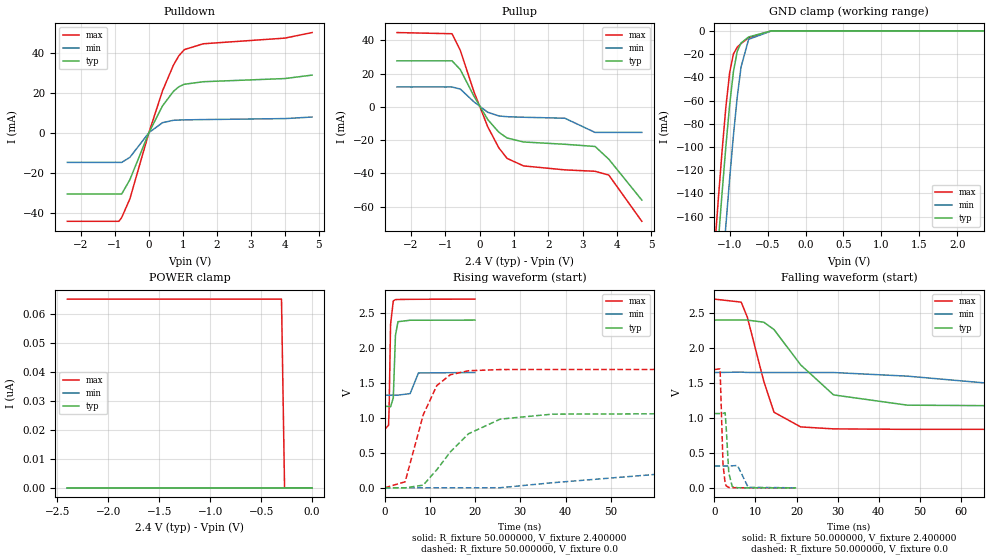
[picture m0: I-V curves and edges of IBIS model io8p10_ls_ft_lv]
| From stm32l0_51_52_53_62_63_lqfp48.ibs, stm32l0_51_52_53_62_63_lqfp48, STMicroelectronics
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|   Model io8p10_ls_ft_lv
[Model]  io8p10_ls_ft_lv
Model_type I/O
Polarity   Non-Inverting
Enable   Active-Low
Vinl =   0.720000V
Vinh =   1.680000V
Vmeas =  1.200000V
Cref =   50.000000pF
Rref =   100.000000M
Vref =   0.0V
C_comp   4.521100pF   4.438000pF   4.578000pF
[Temperature Range]   25.000000   0.105000k   -40.000000
[Pullup Reference]   2.400000V   1.650000V   2.700000V
[Pulldown Reference]   0.0V   0.0V   0.0V
[POWER Clamp Reference]   2.400000V   1.650000V   2.700000V
[GND Clamp Reference]   0.0V   0.0V   0.0V
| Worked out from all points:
|   slope of the pulldown table from 0 to 0.36 V, typ, clamps not added: 29.5 ohm
|   slope of the pullup table from 0 to 0.36 V, typ, clamps not added: 33.2 ohm
|   GND clamp passes 1 mA (typ) near -0.59 V on its own axis
|   rising waveform, R_fixture 50.000000, V_fixture 2.400000: 20-80 % time 360ps typ, 685ps min, 300ps max; typ from 1.17 V to 2.4 V
|   rising waveform, R_fixture 50.000000, V_fixture 0.0: 20-80 % time 9.31ns typ, 24.7ns min, 4.8ns max; typ from 0 V to 1.06 V
|   falling waveform, R_fixture 50.000000, V_fixture 2.400000: 20-80 % time 10.1ns typ, 27.3ns min, 5.05ns max; typ from 2.4 V to 1.17 V
|   falling waveform, R_fixture 50.000000, V_fixture 0.0: 20-80 % time 615ps typ, 996ps min, 511ps max; typ from 1.06 V to 0 V
[Pulldown]
|Voltage   I(typ)   I(min)   I(max)
-2.4V     -30.64mA   -14.84mA   -44.29mA
-880mV    -30.64mA   -14.84mA   -44.29mA
-800mV    -30.64mA   -14.84mA   -42.37mA
-560mV    -23.52mA   -12.34mA   -33.09mA
0V        -765.2nA   -61.1nA    -2.527uA
400mV     13.38mA    4.998mA    20.91mA
720mV     20.62mA    6.178mA    33.69mA
880mV     22.92mA    6.307mA    38.42mA
1.04V     24.19mA    6.385mA    41.49mA
1.6V      25.46mA    6.544mA    44.42mA
4V        27.04mA    7.029mA    47.25mA
4.8V      28.77mA    7.818mA    50.02mA
[Pullup]
|Voltage   I(typ)   I(min)   I(max)
-2.4V     27.74mA    12mA       44.76mA
-800mV    27.74mA    12mA       44.06mA
-560mV    22.49mA    10.76mA    34.07mA
-160mV    6.35mA     2.997mA    8.973mA
240mV     -7.653mA   -3.251mA   -12mA
560mV     -15.22mA   -5.43mA    -24.63mA
800mV     -18.73mA   -5.909mA   -31mA
1.28V     -21.13mA   -6.237mA   -35.54mA
2.48V     -22.51mA   -6.82mA    -37.93mA
3.36V     -23.83mA   -15.37mA   -38.77mA
3.76V     -31.5mA    -15.37mA   -41.06mA
4.72V     -56.1mA    -15.37mA   -68.9mA
[GND_clamp]
|Voltage   I(typ)   I(min)   I(max)
-2.4V     -1.379A    -1.445A    -1.35A
-1.2V     -225.9mA   -297.5mA   -189.2mA
-1.15V    -182mA     -253.1mA   -145.3mA
-1.1V     -139.6mA   -209.7mA   -103.5mA
-1.05V    -99.61mA   -167.6mA   -65.7mA
-1V       -63.67mA   -127.3mA   -35.89mA
-950mV    -35mA      -89.93mA   -19.87mA
-900mV    -17.67mA   -57.01mA   -14.12mA
-850mV    -10.49mA   -31.18mA   -11mA
-750mV    -5.288mA   -7.322mA   -5.997mA
-450mV    -33.57uA   -87.56uA   -14.35uA
2.35V     0A         0A         0A
[POWER_clamp]
|Voltage   I(typ)   I(min)   I(max)
-2.4V     0A         0A         65.17nA
-300mV    0A         0A         65.17nA
-270mV    0A         0A         0A
0V        0A         0A         0A
[Ramp]
| variable   typ   min   max
dV/dt_r  0.63779/9.29730n   0.18781/24.70125n   1.01578/4.79212n
dV/dt_f  0.74034/10.09399n   0.19434/27.26477n   1.11788/5.04027n
R_load = 50.000000
[Rising Waveform]
R_fixture= 50.000000
V_fixture= 2.400000
V_fixture_min= 1.650000
V_fixture_max= 2.700000
|time   V(typ)   V(min)   V(max)
0s        1.166V     1.326V     836.9mV
840.8ps   1.165V     1.326V     895.5mV
961ps     1.164V     1.326V     1.147V
1.281ns   1.16V      1.326V     2.337V
1.882ns   1.286V     1.326V     2.674V
2.362ns   2.183V     1.326V     2.693V
2.923ns   2.377V     1.326V     2.695V
5.606ns   2.398V     1.348V     2.697V
7.447ns   2.398V     1.643V     2.698V
19.94ns   2.4V       1.65V      2.7V
[Rising Waveform]
R_fixture= 50.000000
V_fixture= 0.0
V_fixture_min= 0.0
V_fixture_max= 0.0
|time   V(typ)   V(min)   V(max)
0s        146.2uV    47.36uV    204.6uV
4.505ns   -963.5uV   139uV      85.69mV
8.509ns   38.51mV    -600.6uV   1.045V
11.51ns   258.4mV    -198.7uV   1.463V
14.51ns   513.6mV    -201uV     1.618V
18.52ns   773mV      -174.8uV   1.675V
25.53ns   982.7mV    940.6uV    1.692V
37.04ns   1.054V     71.93mV    1.693V
80.58ns   1.063V     299.7mV    1.693V
249.2ns   1.063V     313mV      1.693V
[Falling Waveform]
R_fixture= 50.000000
V_fixture= 2.400000
V_fixture_min= 1.650000
V_fixture_max= 2.700000
|time   V(typ)   V(min)   V(max)
0s        2.4V       1.65V      2.7V
6.507ns   2.402V     1.656V     2.657V
8.008ns   2.4V       1.651V     2.443V
12.01ns   2.37V      1.65V      1.527V
14.51ns   2.265V     1.65V      1.082V
21.02ns   1.759V     1.65V      872mV
29.03ns   1.33V      1.65V      843.8mV
47.05ns   1.183V     1.598V     837.2mV
95.6ns    1.166V     1.349V     836.9mV
249.2ns   1.166V     1.326V     836.9mV
[Falling Waveform]
R_fixture= 50.000000
V_fixture= 0.0
V_fixture_min= 0.0
V_fixture_max= 0.0
|time   V(typ)   V(min)   V(max)
0s        1.063V     313mV      1.693V
1.361ns   1.063V     313mV      1.703V
2.082ns   1.065V     313mV      335.5mV
2.603ns   1.075V     313mV      62.69mV
2.883ns   836.4mV    313mV      26.23mV
3.483ns   215mV      312.6mV    5.5mV
4.324ns   20.01mV    315.5mV    2.438mV
5.606ns   1.254mV    319.8mV    1.94mV
8.208ns   604.5uV    8.345mV    1.128mV
19.94ns   146.2uV    47.36uV    204.6uV
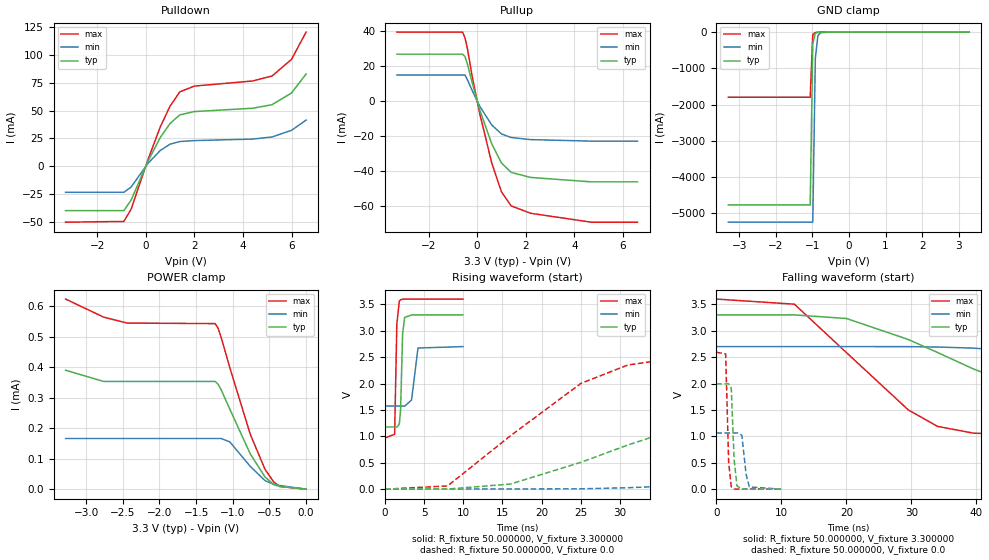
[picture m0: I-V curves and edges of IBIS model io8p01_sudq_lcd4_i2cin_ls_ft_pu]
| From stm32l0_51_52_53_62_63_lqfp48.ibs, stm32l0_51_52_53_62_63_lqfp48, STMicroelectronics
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|   Model io8p01_sudq_lcd4_i2cin_ls_ft_pu
[Model]  io8p01_sudq_lcd4_i2cin_ls_ft_pu
Model_type I/O
Polarity   Non-Inverting
Enable   Active-Low
Vinl =   0.990000V
Vinh =   2.310000V
Vmeas =  1.650000V
Cref =   50.000000pF
Rref =   100.000000M
Vref =   0.0V
C_comp   2.499500pF   2.460800pF   2.557800pF
[Temperature Range]   25.000000   0.125000k   -40.000000
[Pullup Reference]   3.300000V   2.700000V   3.600000V
[Pulldown Reference]   0.0V   0.0V   0.0V
[POWER Clamp Reference]   3.300000V   2.700000V   3.600000V
[GND Clamp Reference]   0.0V   0.0V   0.0V
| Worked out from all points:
|   slope of the pulldown table from 0 to 0.495 V, typ, clamps not added: 22.6 ohm
|   slope of the pullup table from 0 to 0.495 V, typ, clamps not added: 23.9 ohm
|   GND clamp passes 1 mA (typ) near -0.64 V on its own axis
|   rising waveform, R_fixture 50.000000, V_fixture 3.300000: 20-80 % time 216ps typ, 364ps min, 175ps max; typ from 1.18 V to 3.3 V
|   rising waveform, R_fixture 50.000000, V_fixture 0.0: 20-80 % time 27.1ns typ, 59.8ns min, 13.6ns max; typ from 0.001 V to 1.99 V
|   falling waveform, R_fixture 50.000000, V_fixture 3.300000: 20-80 % time 24.2ns typ, 53.5ns min, 13.3ns max; typ from 3.3 V to 1.18 V
|   falling waveform, R_fixture 50.000000, V_fixture 0.0: 20-80 % time 388ps typ, 556ps min, 311ps max; typ from 1.99 V to 0.001 V
[Pulldown]
|Voltage   I(typ)   I(min)   I(max)
-3.3V     -39.83mA   -23.36mA   -50.2mA
-900mV    -39.83mA   -23.36mA   -49.52mA
-600mV    -30.28mA   -18.59mA   -38.45mA
100mV     4.867mA    2.821mA    6.48mA
600mV     25.85mA    14.17mA    35.39mA
1V        38.33mA    19.81mA    53.88mA
1.4V      46.1mA     22.18mA    66.72mA
2V        49.07mA    23.02mA    71.93mA
4.4V      52.05mA    24.38mA    76.53mA
5.2V      55.25mA    26.31mA    81.02mA
6V        65.79mA    32.24mA    95.96mA
6.6V      82.83mA    41.41mA    120.4mA
[Pullup]
|Voltage   I(typ)   I(min)   I(max)
-3.3V     26.78mA    14.88mA    39.37mA
-600mV    26.78mA    14.88mA    39.37mA
-500mV    25.42mA    14.88mA    36.13mA
-400mV    21.16mA    12.2mA     30.01mA
-200mV    10.44mA    5.971mA    13.84mA
100mV     -4.685mA   -2.744mA   -6.647mA
600mV     -24.29mA   -13.56mA   -35.12mA
1V        -35.2mA    -18.69mA   -51.63mA
1.4V      -40.6mA    -20.72mA   -59.71mA
2.2V      -43.48mA   -21.92mA   -63.91mA
4.7V      -46mA      -22.8mA    -69mA
6.6V      -46mA      -22.8mA    -69mA
[GND_clamp]
|Voltage   I(typ)   I(min)   I(max)
-3.3V     -4.766A    -5.244A    -1.797A
-1.06V    -4.766A    -5.244A    -1.797A
-990mV    -326.4mA   -5.244A    -67.85mA
-920mV    -28.83mA   -721.7mA   -11.08mA
-850mV    -6.686mA   -104.1mA   -6.707mA
-780mV    -3.552mA   -17.28mA   -4.326mA
-500mV    -59.41uA   -172uA     -34.91uA
3.28V     0A         0A         0A
[POWER_clamp]
|Voltage   I(typ)   I(min)   I(max)
-3.28V    390.5uA    166.4uA    624.1uA
-2.76V    353.6uA    166.4uA    564.7uA
-2.44V    353.6uA    166.4uA    545.3uA
-1.24V    353.6uA    166.4uA    543.5uA
-1.2V     344.2uA    166.4uA    528.2uA
-1.16V    327.1uA    166.4uA    499.5uA
-1.04V    262.6uA    155.2uA    398.8uA
-760mV    115.1uA    74.4uA     179.3uA
-560mV    39.87uA    27.94uA    65.07uA
-440mV    15uA       15.53uA    23.15uA
-360mV    8.745uA    12.05uA    9.091uA
0V        0A         0A         0A
[Ramp]
| variable   typ   min   max
dV/dt_r  1.19492/27.03086n   0.63593/59.71589n   1.55547/13.56252n
dV/dt_f  1.27344/24.19128n   0.66960/53.47154n   1.57815/13.28528n
R_load = 50.000000
[Rising Waveform]
R_fixture= 50.000000
V_fixture= 3.300000
V_fixture_min= 2.700000
V_fixture_max= 3.600000
|time   V(typ)   V(min)   V(max)
0s        1.178V     1.575V     969.7mV
1.241ns   1.177V     1.575V     1.041V
1.522ns   1.174V     1.575V     3.123V
1.842ns   1.234V     1.575V     3.564V
2.002ns   1.502V     1.575V     3.588V
2.262ns   2.946V     1.574V     3.597V
2.523ns   3.253V     1.571V     3.599V
3.403ns   3.299V     1.69V      3.6V
4.224ns   3.3V       2.673V     3.6V
9.97ns    3.3V       2.7V       3.6V
[Rising Waveform]
R_fixture= 50.000000
V_fixture= 0.0
V_fixture_min= 0.0
V_fixture_max= 0.0
|time   V(typ)   V(min)   V(max)
0s        1.061mV    1.817mV    656.1uV
8.008ns   3.23mV     4.294mV    61.89mV
16.02ns   97.05mV    4.309mV    1.01V
25.03ns   509.1mV    7.344mV    2.003V
31.03ns   837.1mV    27.95mV    2.352V
39.04ns   1.224V     76.22mV    2.519V
57.56ns   1.752V     281.4mV    2.584V
82.08ns   1.948V     592.9mV    2.593V
136.1ns   1.992V     962.5mV    2.593V
249.2ns   1.993V     1.064V     2.593V
[Falling Waveform]
R_fixture= 50.000000
V_fixture= 3.300000
V_fixture_min= 2.700000
V_fixture_max= 3.600000
|time   V(typ)   V(min)   V(max)
0s        3.3V       2.7V       3.6V
12.01ns   3.3V       2.7V       3.503V
20.02ns   3.232V     2.7V       2.585V
29.53ns   2.834V     2.699V     1.5V
34.03ns   2.588V     2.692V     1.189V
39.54ns   2.276V     2.671V     1.061V
56.56ns   1.484V     2.524V     988.2mV
77.08ns   1.262V     2.243V     973.9mV
132.6ns   1.185V     1.706V     969.9mV
249.2ns   1.178V     1.575V     969.7mV
[Falling Waveform]
R_fixture= 50.000000
V_fixture= 0.0
V_fixture_min= 0.0
V_fixture_max= 0.0
|time   V(typ)   V(min)   V(max)
0s        1.993V     1.064V     2.593V
1.441ns   1.993V     1.064V     2.562V
1.902ns   1.997V     1.064V     507.1mV
2.302ns   1.912V     1.064V     45.63mV
2.743ns   553.6mV    1.064V     4.268mV
3.183ns   62.14mV    1.066V     1.281mV
3.924ns   2.803mV    1.024V     858.9uV
4.585ns   1.376mV    275mV      760.9uV
5.085ns   1.256mV    42.52mV    721.9uV
9.97ns    1.061mV    1.817mV    656.1uV
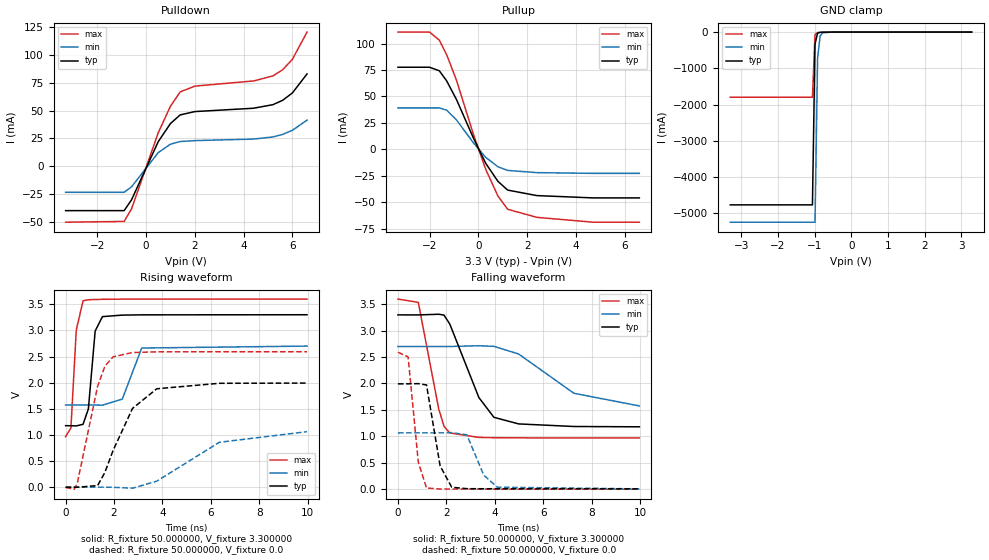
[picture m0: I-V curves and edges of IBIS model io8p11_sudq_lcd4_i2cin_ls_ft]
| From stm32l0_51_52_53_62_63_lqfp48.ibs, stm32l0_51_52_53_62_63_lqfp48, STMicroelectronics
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|   Model io8p11_sudq_lcd4_i2cin_ls_ft
[Model]  io8p11_sudq_lcd4_i2cin_ls_ft
Model_type I/O
Polarity   Non-Inverting
Enable   Active-Low
Vinl =   0.990000V
Vinh =   2.310000V
Vmeas =  1.650000V
Cref =   50.000000pF
Rref =   100.000000M
Vref =   0.0V
C_comp   2.499500pF   2.460800pF   2.557800pF
[Temperature Range]   25.000000   0.125000k   -40.000000
[Pullup Reference]   3.300000V   2.700000V   3.600000V
[Pulldown Reference]   0.0V   0.0V   0.0V
[POWER Clamp Reference]   3.300000V   2.700000V   3.600000V
[GND Clamp Reference]   0.0V   0.0V   0.0V
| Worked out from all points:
|   slope of the pulldown table from 0 to 0.495 V, typ, clamps not added: 22.6 ohm
|   slope of the pullup table from 0 to 0.495 V, typ, clamps not added: 23.9 ohm
|   GND clamp passes 1 mA (typ) near -0.64 V on its own axis
|   rising waveform, R_fixture 50.000000, V_fixture 3.300000: 20-80 % time 218ps typ, 365ps min, 178ps max; typ from 1.18 V to 3.3 V
|   rising waveform, R_fixture 50.000000, V_fixture 0.0: 20-80 % time 1.18ns typ, 2.21ns min, 705ps max; typ from 0 V to 1.99 V
|   falling waveform, R_fixture 50.000000, V_fixture 3.300000: 20-80 % time 1.11ns typ, 2.09ns min, 638ps max; typ from 3.3 V to 1.18 V
|   falling waveform, R_fixture 50.000000, V_fixture 0.0: 20-80 % time 387ps typ, 557ps min, 308ps max; typ from 1.99 V to 0 V
[Pulldown]
|Voltage   I(typ)   I(min)   I(max)
-3.3V     -39.83mA   -23.37mA   -50.2mA
-900mV    -39.83mA   -23.37mA   -49.53mA
-600mV    -30.28mA   -18.59mA   -38.45mA
500mV     22.11mA    12.28mA    30.1mA
1V        38.33mA    19.81mA    53.88mA
1.4V      46.1mA     22.18mA    66.72mA
2V        49.07mA    23.01mA    71.93mA
4.4V      52.05mA    24.38mA    76.53mA
5.2V      55.25mA    26.3mA     81.02mA
5.6V      59.18mA    28.57mA    86.57mA
6V        65.78mA    32.24mA    95.96mA
6.6V      82.83mA    41.41mA    120.4mA
[Pullup]
|Voltage   I(typ)   I(min)   I(max)
-3.3V     77.63mA    39.16mA    110.9mA
-2V       77.63mA    39.16mA    110.9mA
-1.6V     74.23mA    39.16mA    103.2mA
-1.3V     64.66mA    36.99mA    89.44mA
-900mV    47.13mA    27.82mA    65.37mA
-200mV    10.4mA     5.946mA    13.84mA
300mV     -13.29mA   -7.65mA    -18.99mA
800mV     -30.32mA   -16.54mA   -44.19mA
1.2V      -38.62mA   -20mA      -56.79mA
2.4V      -43.84mA   -22.09mA   -64.42mA
4.7V      -46.01mA   -22.8mA    -69mA
6.6V      -46.01mA   -22.8mA    -69mA
[GND_clamp]
|Voltage   I(typ)   I(min)   I(max)
-3.3V     -4.766A    -5.244A    -1.797A
-1.06V    -4.766A    -5.244A    -1.797A
-990mV    -326.4mA   -5.244A    -67.85mA
-920mV    -28.83mA   -721.7mA   -11.08mA
-850mV    -6.686mA   -104.1mA   -6.707mA
-780mV    -3.552mA   -17.28mA   -4.326mA
-500mV    -59.41uA   -172uA     -34.91uA
3.28V     0A         0A         0A
[POWER_clamp]
|Voltage   I(typ)   I(min)   I(max)
-3.28V    0A         0A         0A
0V        0A         0A         0A
[Ramp]
| variable   typ   min   max
dV/dt_r  1.19460/1.17561n   0.61152/2.08443n   1.55562/0.70229n
dV/dt_f  1.27236/1.10950n   0.59466/1.86799n   1.57852/0.63690n
R_load = 50.000000
[Rising Waveform]
R_fixture= 50.000000
V_fixture= 3.300000
V_fixture_min= 2.700000
V_fixture_max= 3.600000
|time   V(typ)   V(min)   V(max)
0s        1.177V     1.573V     966.2mV
220.2ps   1.176V     1.573V     1.135V
440.4ps   1.173V     1.573V     3.005V
720.7ps   1.203V     1.574V     3.566V
940.9ps   1.498V     1.574V     3.587V
1.221ns   2.988V     1.572V     3.592V
1.522ns   3.264V     1.569V     3.595V
2.342ns   3.293V     1.686V     3.599V
3.143ns   3.298V     2.663V     3.599V
9.97ns    3.3V       2.7V       3.6V
[Rising Waveform]
R_fixture= 50.000000
V_fixture= 0.0
V_fixture_min= 0.0
V_fixture_max= 0.0
|time   V(typ)   V(min)   V(max)
0s        169.8uV    8.281uV    -5.703mV
360.4ps   25.99uV    -4.44uV    -38.07mV
480.5ps   -1.029mV   -7.949uV   68.46mV
1.321ns   30.19mV    184.8uV    1.929V
1.622ns   281.5mV    -131.2uV   2.315V
1.962ns   703.5mV    -2.27mV    2.495V
2.763ns   1.507V     -19.44mV   2.577V
3.764ns   1.883V     114.4mV    2.59V
6.346ns   1.988V     859mV      2.592V
9.97ns    1.992V     1.062V     2.592V
[Falling Waveform]
R_fixture= 50.000000
V_fixture= 3.300000
V_fixture_min= 2.700000
V_fixture_max= 3.600000
|time   V(typ)   V(min)   V(max)
0s        3.3V       2.7V       3.6V
840.8ps   3.299V     2.7V       3.538V
1.682ns   3.312V     2.7V       1.521V
1.902ns   3.296V     2.7V       1.187V
2.142ns   3.126V     2.7V       1.06V
3.343ns   1.732V     2.715V     976.6mV
3.964ns   1.357V     2.703V     970.6mV
4.985ns   1.232V     2.558V     967.5mV
7.267ns   1.183V     1.813V     966.4mV
9.97ns    1.177V     1.573V     966.2mV
[Falling Waveform]
R_fixture= 50.000000
V_fixture= 0.0
V_fixture_min= 0.0
V_fixture_max= 0.0
|time   V(typ)   V(min)   V(max)
0s        1.992V     1.062V     2.592V
420.4ps   1.992V     1.062V     2.503V
840.8ps   1.996V     1.062V     506.1mV
1.181ns   1.971V     1.062V     16.01mV
1.742ns   436mV      1.062V     -2.685mV
2.222ns   30.3mV     1.066V     -3.72mV
2.843ns   3.698mV    1.027V     -4.586mV
3.544ns   2.191mV    260.3mV    -5.156mV
4.104ns   1.537mV    31.52mV    -5.395mV
9.97ns    169.8uV    8.281uV    -5.703mV
